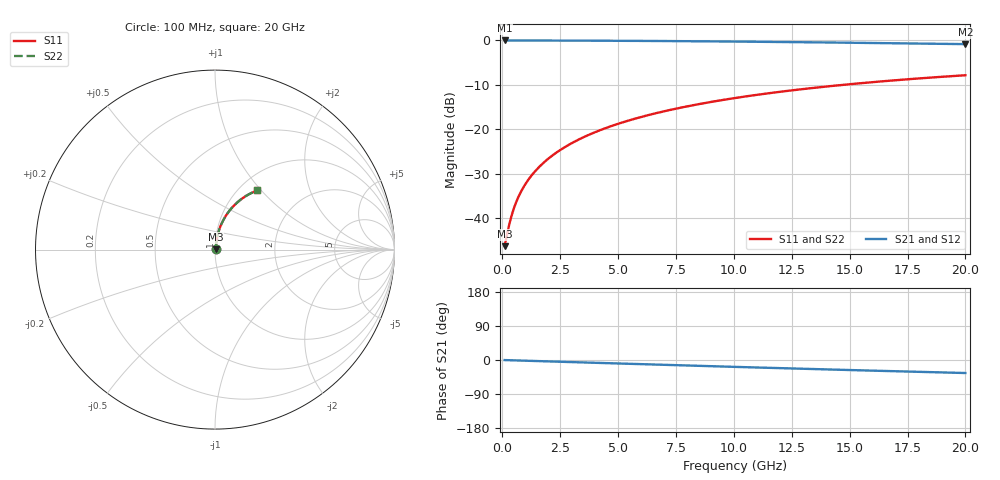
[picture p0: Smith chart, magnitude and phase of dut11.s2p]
! Touchstone file exported from HFSS 2026.1.0
!  File:  C:/ffzhzh/LocalFiles/Ansys_Project_Files/temp_test_BSMRDL_11_1782907343_42304.aedt
!  Generated:  08:03:36 PM Jul  1, 2026
!  Design:  BSMRDL
!  Project:  temp_test_BSMRDL_11_1782907343_42304
! Variables:
!  h_bsmrdl = 2.03um
!  h_ox = 20um
!  h_rdl = 5um
!  h_sub = 80um
!  h_tmrdl = 5um
!  h_tsv = 80um
!  h_via = 3um
!  l_bsmrdl = 400.32um
!  l_sub = 800.32um
!  l_tmrdl = 200um
!  m_sub = 200um
!  pitch = 58.43um
!  r_tsv = 6um
!  s_tmrdl = 10um
!  w_bsmrdl = 17.83um
!  w_sub = 500um
!  w_tmrdl = 12um
!  x_tsv_center1 = 206um
!  x_tsv_center2 = 624.15um
!  x_tsv_center3 = 836.15um
!  x_tsv_center4 = 1254.3um
!  x_tsv_center5 = 1466.3um
!  x_tsv_center6 = 1884.45um
# GHz S MA R 50.000000
! Terminal data exported
! Port[1] = BSM_RDL1_1_T1
! Port[2] = BSM_RDL1_1_T2
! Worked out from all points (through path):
!   200 points, 100 MHz to 20 GHz, reference 50 ohm
!   highest |S21| = -0.04 dB at 100 MHz (marker M1); lowest = -0.9 dB at 20 GHz (marker M2)
!   group delay of S21, straight-line fit = 4.79 ps
!   lowest |S11| = -46.2 dB at 100 MHz (marker M3), VSWR 1.01, Z = 50.4 + j0.248 ohm
!   |S11| at or under -10 dB: start of sweep to 14.73 GHz
!   |S22| runs from -46.2 to -7.8 dB; largest |S21 - S12| = 4.4e-15
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0.1  0.004885 30.2  0.9958 -0.2  0.9958 -0.2  0.004885 30.2
! Gamma 0 0 0 0
! Port Impedance 50 0 50 0
0.3  0.008546 59.0  0.9956 -0.6  0.9956 -0.6  0.008546 59.0
0.4  0.01073 64.9  0.9955 -0.8  0.9955 -0.8  0.01073 64.9
0.5  0.01298 68.7  0.9954 -1.0  0.9954 -1.0  0.01298 68.7
0.6  0.01525 71.3  0.9953 -1.1  0.9953 -1.1  0.01525 71.3
0.8  0.01981 74.5  0.995 -1.5  0.995 -1.5  0.01981 74.5
1.1  0.02664 77.2  0.9947 -2.1  0.9947 -2.1  0.02664 77.2
1.3  0.0312 78.2  0.9945 -2.4  0.9945 -2.4  0.0312 78.2
1.5  0.03576 78.9  0.9942 -2.8  0.9942 -2.8  0.03576 78.9
1.8  0.04261 79.6  0.9939 -3.3  0.9939 -3.3  0.04261 79.6
2.1  0.04947 79.9  0.9935 -3.9  0.9935 -3.9  0.04947 79.9
2.7  0.0632 80.1  0.9926 -5.0  0.9926 -5.0  0.0632 80.1
3.5  0.08146 79.6  0.9912 -6.5  0.9912 -6.5  0.08146 79.6
4.2  0.09738 78.9  0.9896 -7.7  0.9896 -7.7  0.09738 78.9
5  0.1154 77.9  0.9876 -9.2  0.9876 -9.2  0.1154 77.9
5.9  0.1356 76.7  0.9849 -10.8  0.9849 -10.8  0.1356 76.7
6.8  0.1555 75.3  0.9818 -12.4  0.9818 -12.4  0.1555 75.3
8.3  0.188 73.0  0.9758 -15.1  0.9758 -15.1  0.188 73.0
10.1  0.2259 70.0  0.9674 -18.3  0.9674 -18.3  0.2259 70.0
13.4  0.2914 64.7  0.9492 -23.9  0.9492 -23.9  0.2914 64.7
16.7  0.3513 59.4  0.9281 -29.2  0.9281 -29.2  0.3513 59.4
20  0.4053 54.4  0.9055 -34.3  0.9055 -34.3  0.4053 54.4
